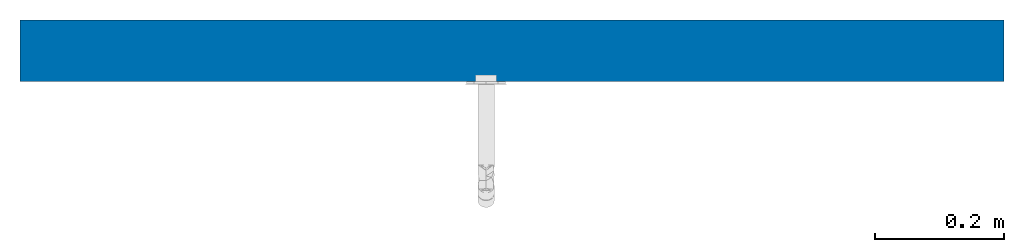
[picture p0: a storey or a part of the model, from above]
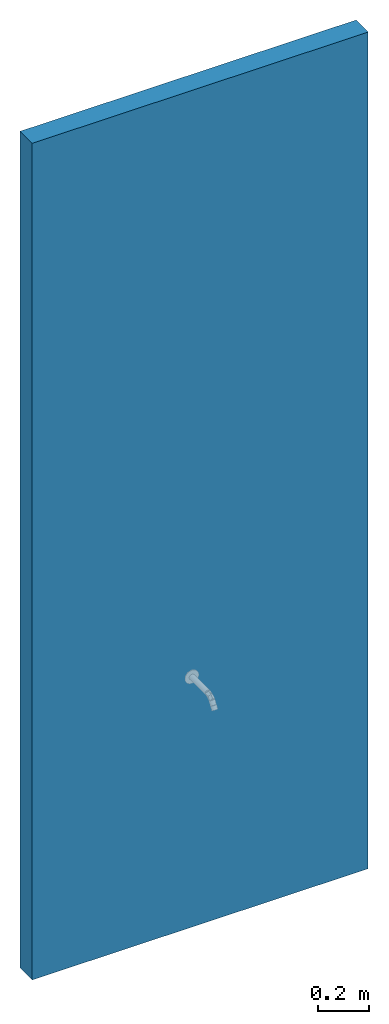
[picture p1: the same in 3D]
Properties of the parts of a building model (IFC2X3)

# File
Description: ViewDefinition [CoordinationView]
File name: Project Number
Time: 2019-04-25T11:27:24
Written by: The EXPRESS Data Manager Version 5.02.0100.07 : 28 Aug 2013
Made in: 20140606_1530(x64) - Exporter 2015.0.2014.0606 - Default UI
Comment: STEP Physical File produced by: The EXPRESS Data Manager Version 5.02.0100.07 : 28 Aug 2013 * Module: EDMstepFileFactory/EDMstandAlone * Creation date: Thu Apr 25 11:27:24 2019 * Host: SarahSams-HP * Database: C:\Users\SARAHS~1\AppData\Local\Temp\{7630C65A-3E0B-453A-904B-4850CE943E7B}\ifc * Database version: 5507 * Database creation date: Thu Apr 25 11:27:23 2019 * Schema: IFC2X3 * Model: DataRepository.ifc * Model creation date: Thu Apr 25 11:27:23 2019 * Header model: DataRepository.ifc_HeaderModel * Header model creation date: Thu Apr 25 11:27:24 2019 * EDMuser: sdai-user * EDMgroup: sdai-group * License ID and type: 5605 : Permanent license. Expiry date: * EDMstepFileFactory options: 020000

# IfcProject, Project Number
LongName: Project Name; Phase: Project Status

# IfcSite, Default
RefLatitude: 51, 30, 0, 549316; RefLongitude: 0, -7, -34, -450321; RefElevation: 0 mm
Other - Category: Project Information; Client Name: Owner; Project Address: Enter address here; Project Issue Date: Issue Date; Project Name: Project Name; Project Number: Project Number; Project Status: Project Status

# IfcBuilding
Pset_BuildingCommon - NumberOfStoreys: 1
Other - Category: Project Information; Client Name: Owner; Project Address: Enter address here; Project Issue Date: Issue Date; Project Name: Project Name; Project Number: Project Number; Project Status: Project Status

# IfcBuildingStorey, Level 0
LongName: Level 0; Elevation: 0 mm
Other - Category: Levels; Family Name: Level; Family: Level: Circle Head - Project Datum; Family and Type: Level: Circle Head - Project Datum; Type: Level: Circle Head - Project Datum; Type Id: Level: Circle Head - Project Datum
Identity Data - Type Name: Circle Head - Project Datum; Structural: no; Building Story: yes; Name: Level 0
Constraints - Elevation: 0 mm; Elevation Base: Project Base Point
Dimensions - Computation Height: 0 mm
Graphics - Color: 0; Line Pattern: Centre; Line Weight: 1; Symbol: Anno_Level_Head_Circle: Standard; Symbol at End 1 Default: yes; Symbol at End 2 Default: no

# IfcFlowController: Battery Pack Brushed Stainless Steel, Duten_WtrSplyFitngsForWshBsnsAndTrghs_R335:Battery Pack Brushed Stainless Steel:262264
In: Level 0
Type - PredefinedType: FAUCET; Classification: C1030210 Bath & Toilet Accessories - Commercial (Uniformat); Material: Duten_Metal_BrushedStainlessSteel, Duten_Plastic_Black
Type - Constraints - Default Elevation: 1200 mm
Type - General - Author: Diane Butterworth Ltd; ManufacturerName: Duten; ManufacturerURL: http://www.duten.fr/; NBSDescription: Taps and water supply fittings for wash basins and troughs; NBSReference: 45-35-70/371; ProductInformation: https://www.duten.fr/produits/robinetterie/robinet-electronique-r310; Revision: n/a; Uniclass2015Code: Pr_40_20_87_98; Uniclass2015Title: Washbasin taps; Uniclass2015Version: Pr-Products v1.10
Type - Identity Data - Assembly Code: C1030210; Assembly Description: Bath & Toilet Accessories - Commercial; Cost: 0; Description: Battery Pack Brushed Stainless Steel; Keynote: Pr_40_20_87_98; Manufacturer: Duten; Model: R335-S_BAT; Type Comments: Battery Pack Brushed Stainless Steel; Type Name: Battery Pack Brushed Stainless Steel; URL: http://www.duten.fr/
Type - Materials and Finishes - SensorFinish: Duten_Plastic_Black; TapFinish: Duten_Metal_BrushedStainlessSteel
Type - Other - AccessibilityPerformance: n/a; AssetIdentifier: n/a; AssetType: Moveable; BarCode: n/a; Category: Pr_40_20_87_98: Washbasin taps; CodePerformance: WRAS Approved. ASME A112.18.1-2011/CSA B125.1-11; Color: Defined by Finish; Constituents: Stainless Steel Stem, Touchless Sensor, Concealed Battery Power; DurationUnit: Years; ExpectedLife: 10; Family Name: Duten_WtrSplyFitngsForWshBsnsAndTrghs_R335; Features: Electronic wall-mounted tap, with automatic detection, for pre-mixed or cold water. Flow rate preset at 3l/min but available in flow rates of 1.3l/min, 1.89l/min, 4l/min or 6l/min; Finish: Brushed, Polished or Matte Black Stainless Steel Available; Grade: n/a; InstallationDate: 1900-12-31T23:59:59; Material: Stainless Steel; ModelNumber: R335-S_BAT; ModelReference: Battery Pack Brushed Stainless Steel; Name: WaterSupplyFittingsForWashBasinsAndTroughs_R335_Duten; ReplacementCost: 0; SerialNumber: n/a; Shape: Cylindrical; Size: (H) 170mm x (L) 150mm x (W) 45mm; SustainabilityPerformance: n/a; TagNumber: n/a; WarrantyDescription: n/a; WarrantyDurationLabor: contact@duten.fr; WarrantyDurationParts: contact@duten.fr; WarrantyDurationUnit: Years; WarrantyGuarantorLabor: 10; WarrantyGuarantorParts: 10; WarrantyStartDate: 1900-12-31T23:59:59
Type - Plumbing - CW Connection: yes; FlowRate: 3L/min; HW Connection: yes; Vent Connection: no; Waste Connection: no; WaterSupplyTemperatureMaximum: 70 °C
Pset_ManufacturerTypeInformation - ModelReference: Battery Pack Brushed Stainless Steel; Manufacturer: Duten
Pset_DistributionFlowElementCommon - Reference: n/a
Constraints - Elevation: 1200 mm; Host: Basic Wall : Wall-Partn_12P-70MStd-12P; Level: Level: Level 0
Dimensions - Area: 0.0124674 m2; Volume: 0.000117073 m3
Identity Data - Mark: 8
Mechanical - System Classification: Other,Controls
Other - Category: Plumbing Fixtures; Family: Duten_WtrSplyFitngsForWshBsnsAndTrghs_R335: Battery Pack Brushed Stainless Steel; Family and Type: Duten_WtrSplyFitngsForWshBsnsAndTrghs_R335: Battery Pack Brushed Stainless Steel; Schedule Level: Level: Level 0; Type: Duten_WtrSplyFitngsForWshBsnsAndTrghs_R335: Battery Pack Brushed Stainless Steel; Type Id: Duten_WtrSplyFitngsForWshBsnsAndTrghs_R335: Battery Pack Brushed Stainless Steel
Phasing - Phase Created: New Construction

# IfcWallStandardCase: Basic Wall:Wall-Partn_12P-70MStd-12P, Basic Wall:Wall-Partn_12P-70MStd-12P:261433
In: Level 0
Type - PredefinedType: STANDARD; Material: Plaster 12.5 mm, Metal Stud Layer 70 mm, Plaster 12.5 mm
Type - Analytical Properties - Absorptance: 0.7; Heat Transfer Coefficient (U): 0.350998; Roughness: 3; Thermal mass: 26964.3; Thermal Resistance (R): 2.84902
Type - Construction - Function: Interior; Width: 95 mm; Wrapping at Inserts: Both
Type - Graphics - Coarse Scale Fill Color: 12632256; Coarse Scale Fill Pattern: Solid fill
Type - Identity Data - Type Name: Wall-Partn_12P-70MStd-12P
Type - Other - Category: Walls; Family Name: Basic Wall
Constraints - Base Constraint: Level: Level 0; Base Extension Distance: 0 mm; Base is Attached: no; Base Offset: 0 mm; Location Line: Wall Centerline; Related to Mass: no; Room Bounding: yes; Top Constraint: Level: Level 1; Top Extension Distance: 0 mm; Top is Attached: no; Top Offset: 0 mm; Unconnected Height: 4000 mm
Dimensions - Area: 6.08 m2; Length: 1520 mm; Volume: 0.5776 m3
Other - Family: Basic Wall: Wall-Partn_12P-70MStd-12P; Family and Type: Basic Wall: Wall-Partn_12P-70MStd-12P; Type: Basic Wall: Wall-Partn_12P-70MStd-12P; Type Id: Basic Wall: Wall-Partn_12P-70MStd-12P
Phasing - Phase Created: New Construction
Structural - Enable Analytical Model: no; Structural: no; Structural Usage: Non-bearing
Pset_WallCommon - Reference: Wall-Partn_12P-70MStd-12P; LoadBearing: no; ExtendToStructure: no; IsExternal: no; ThermalTransmittance: 0.350998 kg/K/s3
